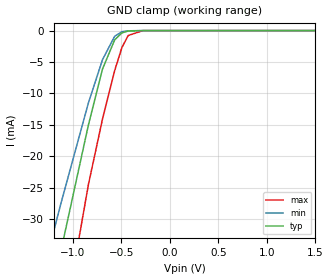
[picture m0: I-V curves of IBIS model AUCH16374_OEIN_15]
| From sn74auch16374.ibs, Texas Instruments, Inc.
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[Model]   AUCH16374_OEIN_15
Model_type  Input
Vinl=0.49
Vinh=1.04
| variable   typ   min   max
C_comp   2.48pF   2.04pF   2.85pF
[Temperature Range]   40   100   -40
| Ambient temperature   25   85   -40
[Voltage range]   1.5   1.4   1.6
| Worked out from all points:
|   GND clamp passes 1 mA (typ) near -0.55 V on its own axis
[GND Clamp]
| AUCH16374_OEIN_15
|   Voltage   I(typ)   I(min)   I(max)
-3.6V     -222.3mA   -186.1mA   -267.5mA
-1.505V   -63.42mA   -50.72mA   -83.44mA
-1.325V   -49.94mA   -39.61mA   -67.39mA
-1.17V    -38.46mA   -30.25mA   -53.55mA
-1.12V    -34.79mA   -27.28mA   -49.08mA
-840mV    -14.98mA   -11.48mA   -24.46mA
-695mV    -6.114mA   -4.621mA   -14.06mA
-570mV    -1.487mA   -911.6uA   -6.381mA
-495mV    -364.6uA   -178.8uA   -2.692mA
-430mV    -73.19uA   -34.73uA   -776.9uA
-280mV    -781.4nA   -556.3nA   -5.358uA
1.5V      165.9pA    258.5pA    172.1pA
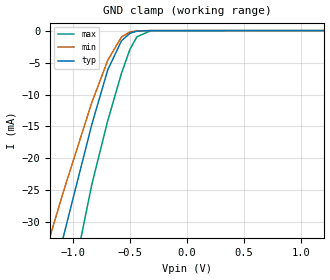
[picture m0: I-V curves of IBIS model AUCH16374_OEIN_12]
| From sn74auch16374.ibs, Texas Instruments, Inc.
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[Model]   AUCH16374_OEIN_12
Model_type  Input
Vinl=0.385
Vinh=0.845
| variable   typ   min   max
C_comp   2.51pF   2.11pF   2.86pF
[Temperature Range]   40   100   -40
| Ambient temperature   25   85   -40
[Voltage range]   1.2   1.1   1.3
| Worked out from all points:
|   GND clamp passes 1 mA (typ) near -0.55 V on its own axis
[GND Clamp]
| AUCH16374_OEIN_12
|   Voltage   I(typ)   I(min)   I(max)
-3.6V     -222.3mA   -186.1mA   -267.5mA
-1.445V   -58.91mA   -46.99mA   -78.09mA
-1.275V   -46.22mA   -36.57mA   -62.93mA
-1.11V    -34.06mA   -26.69mA   -48.19mA
-1.075V   -31.52mA   -24.64mA   -45.06mA
-835mV    -14.65mA   -11.22mA   -24.05mA
-695mV    -6.114mA   -4.621mA   -14.06mA
-575mV    -1.603mA   -998.8uA   -6.664mA
-500mV    -407.1uA   -201.6uA   -2.896mA
-440mV    -95.43uA   -45.03uA   -977.4uA
-320mV    -2.85uA    -1.742uA   -25.53uA
1.2V      133.3pA    223pA      123.7pA
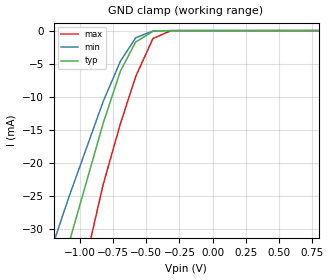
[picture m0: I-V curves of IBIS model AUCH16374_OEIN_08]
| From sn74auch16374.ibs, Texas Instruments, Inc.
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[Model]   AUCH16374_OEIN_08
Model_type  Input
Vinl=0
Vinh=0.8
| variable   typ   min   max
C_comp   2.54pF   2.21pF   2.84pF
[Temperature Range]   40   100   -40
| Ambient temperature   25   85   -40
[Voltage range]   0.8   0.8   0.8
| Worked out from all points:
|   GND clamp passes 1 mA (typ) near -0.55 V on its own axis
[GND Clamp]
| AUCH16374_OEIN_08
|   Voltage   I(typ)   I(min)   I(max)
-3.6V     -222.3mA   -186.1mA   -267.5mA
-1.455V   -59.66mA   -47.61mA   -78.99mA
-1.32V    -49.56mA   -39.31mA   -66.95mA
-1.275V   -46.22mA   -36.57mA   -62.93mA
-1.115V   -34.43mA   -26.99mA   -48.63mA
-1.08V    -31.88mA   -24.93mA   -45.51mA
-825mV    -13.98mA   -10.7mA    -23.23mA
-695mV    -6.114mA   -4.621mA   -14.06mA
-580mV    -1.724mA   -1.092mA   -6.949mA
-450mV    -123.7uA   -58.25uA   -1.212mA
-315mV    -2.431uA   -1.513uA   -21.15uA
800mV     96.17pA    179.1pA    76.88pA
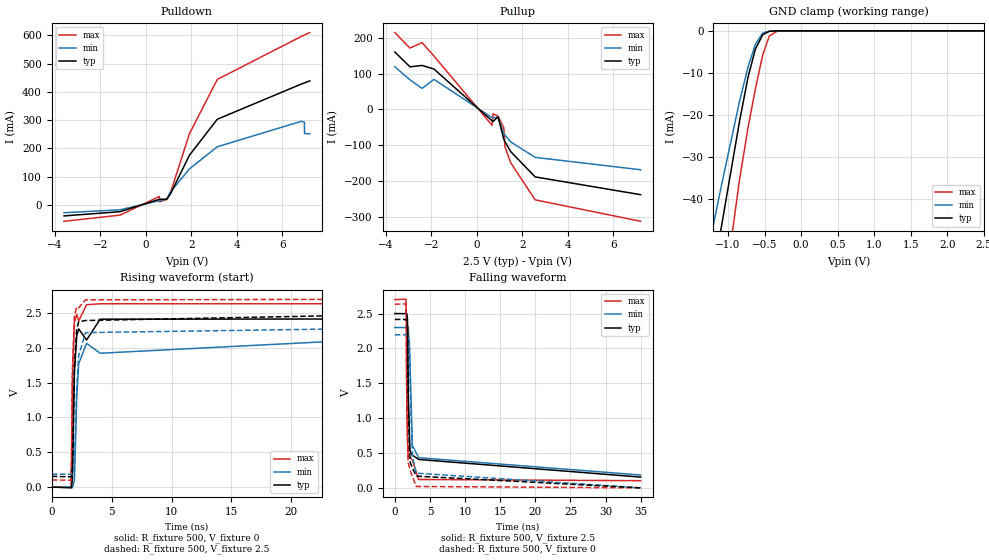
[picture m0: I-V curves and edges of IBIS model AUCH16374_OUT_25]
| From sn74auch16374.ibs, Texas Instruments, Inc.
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[Model]   AUCH16374_OUT_25
Model_type  3-state
Enable   Active-Low
Vref =   0
Rref =   500
Cref =   30p
Vmeas =   1.25
| variable   typ   min   max
C_comp   5.21pF   4.67pF   5.45pF
| C_pullup   7.72pF   4.63pF   11.90pF
| C_pulldown   6.68pF   4.66pF   15.29pF
| C_tri-state   5.21pF   4.67pF   5.45pF
[Temperature Range]   40   100   -40
| Ambient temperature   25   85   -40
[Voltage range]   2.5   2.3   2.7
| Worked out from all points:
|   slope of the pulldown table from 0 to 0.375 V, typ, clamps not added: 30.7 ohm
|   slope of the pullup table from 0 to 0.375 V, typ, clamps not added: 19 ohm
|   GND clamp passes 1 mA (typ) near -0.53 V on its own axis
|   rising waveform, R_fixture 500, V_fixture 0: 20-80 % time 202ps typ, 281ps min, 145ps max; typ from 0 V to 2.42 V
|   falling waveform, R_fixture 500, V_fixture 2.5: 20-80 % time 248ps typ, 345ps min, 180ps max; typ from 2.5 V to 0.154 V
|   rising waveform, R_fixture 500, V_fixture 2.5: 20-80 % time 206ps typ, 288ps min, 146ps max; typ from 0.154 V to 2.5 V
|   falling waveform, R_fixture 500, V_fixture 0: 20-80 % time 269ps typ, 377ps min, 184ps max; typ from 2.42 V to 0 V
[GND Clamp]
| AUCH16374_OUT_25
|   Voltage   I(typ)   I(min)   I(max)
-3.6V     -318.7mA   -267.2mA   -388.7mA
-1.515V   -91.86mA   -73.92mA   -122.2mA
-1.455V   -85.39mA   -68.57mA   -114.5mA
-1.295V   -68.26mA   -54.47mA   -93.72mA
-1.105V   -48.18mA   -38.11mA   -69.04mA
-840mV    -21.35mA   -16.65mA   -35.22mA
-725mV    -11mA      -8.581mA   -23.02mA
-625mV    -4.332mA   -3.19mA    -13.84mA
-525mV    -969.3uA   -536.9uA   -5.77mA
-435mV    -119.4uA   -67.05uA   -1.249mA
-325mV    -4.914uA   -5.522uA   -43.94uA
2.5V      1.045nA    211.8nA    1.502nA
[Pulldown]
| AUCH16374_OUT_25
|   Voltage   I(typ)   I(min)   I(max)
-3.6V     -38.75mA   -27.46mA   -57.79mA
-1.14V    -23.79mA   -17.18mA   -36mA
590mV     19.92mA    14.98mA    30.03mA
600mV     20.28mA    15.25mA    11.17mA
910mV     20.16mA    20.33mA    19.24mA
1.07V     37.88mA    45.66mA    41.07mA
1.915V    176.4mA    127.8mA    252.5mA
3.135V    303.2mA    205.9mA    444mA
6.825V    427.7mA    295.8mA    596.2mA
6.965V    431.9mA    293mA      601.3mA
6.97V     432.1mA    252.7mA    601.5mA
7.2V      439mA      251.9mA    609.9mA
[Pullup]
| AUCH16374_OUT_25
|   Voltage   I(typ)   I(min)   I(max)
-3.6V     160mA      119mA      214.2mA
-2.935V   118.6mA    82.49mA    170.9mA
-2.405V   122.6mA    58.64mA    186.2mA
-1.88V    112.5mA    83.79mA    148.8mA
670mV     -31.69mA   -22.93mA   -44.2mA
720mV     -33.47mA   -24.18mA   -12.23mA
935mV     -20.74mA   -21.43mA   -18.64mA
1.19V     -83.17mA   -67.47mA   -51.41mA
1.235V    -89.46mA   -71.21mA   -103.5mA
1.49V     -117.6mA   -90.51mA   -148.5mA
2.565V    -188.1mA   -133.7mA   -252.1mA
7.2V      -237.7mA   -168.2mA   -311.9mA
[Ramp]
| AUCH16374_OUT_25
| variable   typ   min   max
dV/dt_r   1.46/2.03E-10   1.33/2.84E-10   1.59/1.46E-10
dV/dt_f   1.41/2.50E-10   1.27/3.50E-10   1.56/1.81E-10
R_load = 500
[Rising Waveform]
| AUCH16374_OUT_25
R_fixture =   500
C_fixture =   0
L_fixture =   0
V_fixture =   0
V_fixture_min = 0
V_fixture_max = 0
|   Time   V(typ)   V(min)   V(max)
0s        12.33nV    36.82nV    2.005nV
1.605ns   -8.878mV   960uV      -6.308mV
1.65ns    -10.62mV   -921uV     261.7mV
1.73ns    122mV      -8.948mV   1.584V
1.895ns   1.639V     93.43mV    2.368V
2.09ns    2.175V     1.296V     2.481V
2.255ns   2.272V     1.774V     2.387V
2.905ns   2.113V     2.065V     2.62V
4.045ns   2.412V     1.923V     2.633V
34.99ns   2.416V     2.195V     2.634V
[Falling Waveform]
| AUCH16374_OUT_25
R_fixture =   500
C_fixture =   0
L_fixture =   0
V_fixture =   2.5
V_fixture_min = 2.3
V_fixture_max = 2.7
|   Time   V(typ)   V(min)   V(max)
0s        2.5V       2.3V       2.7V
1.585ns   2.499V     2.3V       2.707V
1.64ns    2.498V     2.3V       2.436V
1.71ns    2.5V       2.3V       1.196V
1.8ns     2.423V     2.299V     749.3mV
1.915ns   1.301V     2.298V     425.9mV
2.16ns    525.1mV    1.817V     441.9mV
2.495ns   469.6mV    609.5mV    397.7mV
3.395ns   407.3mV    432.3mV    120.3mV
34.99ns   154.5mV    184.4mV    102.7mV
[Rising Waveform]
| AUCH16374_OUT_25
R_fixture =   500
C_fixture =   0
L_fixture =   0
V_fixture =   2.5
V_fixture_min = 2.3
V_fixture_max = 2.7
|   Time   V(typ)   V(min)   V(max)
0s        154.5mV    184.4mV    102.6mV
1.605ns   147.4mV    185.2mV    99.53mV
1.65ns    148.6mV    183.8mV    388.7mV
1.71ns    225.9mV    179.5mV    1.425V
1.74ns    377.9mV    177.6mV    1.744V
1.89ns    1.706V     305.5mV    2.441V
2.075ns   2.257V     1.371V     2.589V
2.245ns   2.374V     1.884V     2.576V
2.82ns    2.393V     2.219V     2.69V
34.99ns   2.5V       2.3V       2.7V
[Falling Waveform]
| AUCH16374_OUT_25
R_fixture =   500
C_fixture =   0
L_fixture =   0
V_fixture =   0
V_fixture_min = 0
V_fixture_max = 0
|   Time   V(typ)   V(min)   V(max)
0s        2.416V     2.195V     2.634V
1.585ns   2.415V     2.195V     2.639V
1.71ns    2.414V     2.195V     1.151V
1.805ns   2.306V     2.194V     657.2mV
1.9ns     1.373V     2.192V     360.8mV
2.075ns   589.7mV    2.099V     293.3mV
2.2ns     363.5mV    1.381V     253.2mV
2.52ns    280.7mV    446mV      157mV
3.06ns    168.3mV    210.8mV    19.86mV
34.99ns   28.62uV    1.369uV    13.32uV
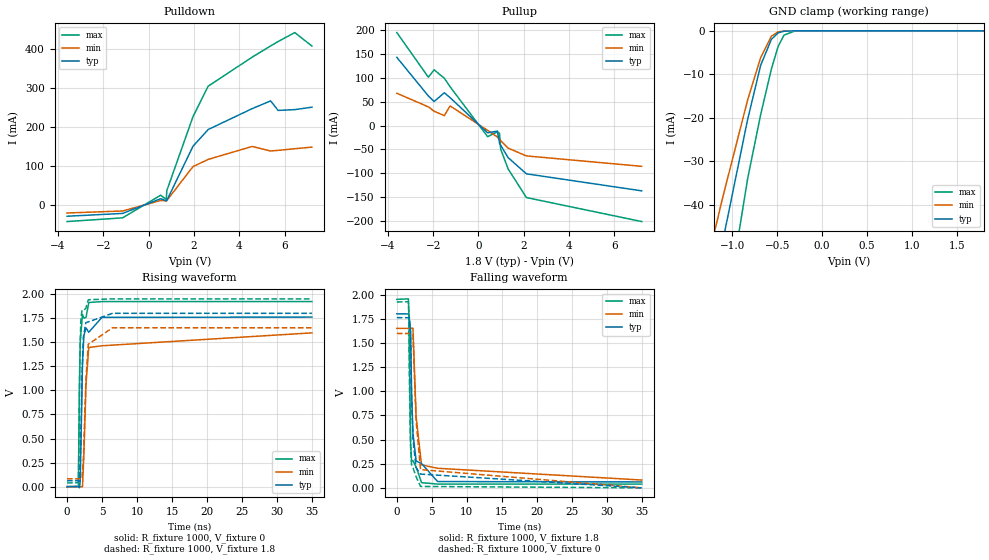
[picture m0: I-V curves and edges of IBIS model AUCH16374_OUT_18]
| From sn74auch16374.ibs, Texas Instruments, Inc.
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[Model]   AUCH16374_OUT_18
Model_type  3-state
Enable   Active-Low
Vref =   0
Rref =   1000
Cref =   30p
Vmeas =   0.9
| variable   typ   min   max
C_comp   5.42pF   4.87pF   5.64pF
| C_pullup   6.28pF   0.99pF   11.81pF
| C_pulldown   6.13pF   3.50pF   13.44pF
| C_tri-state   5.42pF   4.87pF   5.64pF
[Temperature Range]   40   100   -40
| Ambient temperature   25   85   -40
[Voltage range]   1.8   1.65   1.95
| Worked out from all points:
|   slope of the pulldown table from 0 to 0.27 V, typ, clamps not added: 34.2 ohm
|   slope of the pullup table from 0 to 0.27 V, typ, clamps not added: 24.9 ohm
|   GND clamp passes 1 mA (typ) near -0.53 V on its own axis
|   rising waveform, R_fixture 1000, V_fixture 0: 20-80 % time 313ps typ, 474ps min, 203ps max; typ from 0 V to 1.76 V
|   falling waveform, R_fixture 1000, V_fixture 1.8: 20-80 % time 399ps typ, 621ps min, 241ps max; typ from 1.8 V to 0.061 V
|   rising waveform, R_fixture 1000, V_fixture 1.8: 20-80 % time 310ps typ, 474ps min, 201ps max; typ from 0.061 V to 1.8 V
|   falling waveform, R_fixture 1000, V_fixture 0: 20-80 % time 398ps typ, 625ps min, 241ps max; typ from 1.76 V to 0 V
[GND Clamp]
| AUCH16374_OUT_18
|   Voltage   I(typ)   I(min)   I(max)
-3.6V     -318.7mA   -267.2mA   -388.7mA
-1.48V    -88.08mA   -70.8mA    -117.7mA
-1.435V   -83.24mA   -66.8mA    -111.9mA
-1.3V     -68.79mA   -54.91mA   -94.37mA
-1.105V   -48.18mA   -38.11mA   -69.04mA
-830mV    -20.4mA    -15.9mA    -34.03mA
-685mV    -7.944mA   -6.173mA   -19.28mA
-565mV    -1.95mA    -1.225mA   -8.764mA
-490mV    -463.8uA   -241.2uA   -3.576mA
-425mV    -91.37uA   -53.49uA   -985.3uA
-300mV    -2.288uA   -2.897uA   -16.98uA
1.8V      674.8pA    45.17nA    747.9pA
[Pulldown]
| AUCH16374_OUT_18
|   Voltage   I(typ)   I(min)   I(max)
-3.6V     -28.49mA   -20.22mA   -42.08mA
-1.15V    -21.28mA   -15.02mA   -32.6mA
530mV     16.28mA    11.83mA    25.26mA
780mV     11.06mA    10.81mA    14.1mA
800mV     11.7mA     11.72mA    36.72mA
1.955V    150.3mA    98.42mA    225.9mA
2.625V    193.2mA    116.8mA    304mA
4.56V     246.5mA    149.9mA    378.1mA
5.38V     266.4mA    138.3mA    406.9mA
5.71V     242.1mA    140mA      418.2mA
6.445V    244.1mA    144.1mA    441.1mA
7.2V      250.4mA    148.3mA    406.7mA
[Pullup]
| AUCH16374_OUT_18
|   Voltage   I(typ)   I(min)   I(max)
-3.6V     143.4mA    67.81mA    195.5mA
-2.21V    62.22mA    39.25mA    101.7mA
-1.955V   50.53mA    30.07mA    117.2mA
-1.505V   68.89mA    20.87mA    99.46mA
-1.25V    58.62mA    41.27mA    81.57mA
405mV     -15.38mA   -10.2mA    -23.47mA
835mV     -11.64mA   -24.19mA   -13.09mA
930mV     -37.45mA   -29.05mA   -16.21mA
980mV     -41.44mA   -31.73mA   -49.64mA
1.31V     -67.6mA    -47.58mA   -91.39mA
2.115V    -101.6mA   -63.91mA   -151.5mA
7.2V      -137.4mA   -85.82mA   -202mA
[Ramp]
| AUCH16374_OUT_18
| variable   typ   min   max
dV/dt_r   1.06/3.19E-10   0.97/4.78E-10   1.15/2.05E-10
dV/dt_f   1.05/4.00E-10   0.95/6.22E-10   1.15/2.43E-10
R_load = 1000
[Rising Waveform]
| AUCH16374_OUT_18
R_fixture =   1000
C_fixture =   0
L_fixture =   0
V_fixture =   0
V_fixture_min = 0
V_fixture_max = 0
|   Time   V(typ)   V(min)   V(max)
0s        9.675nV    33.63nV    1.209nV
1.625ns   1.147mV    591.7uV    3.39mV
1.78ns    -12.14mV   1.509mV    1.042V
1.89ns    62.48mV    54.87uV    1.513V
2.21ns    1.275V     -292.6uV   1.788V
2.41ns    1.569V     336.3mV    1.75V
2.72ns    1.648V     1.068V     1.758V
3.105ns   1.603V     1.445V     1.912V
4.99ns    1.758V     1.463V     1.922V
34.99ns   1.761V     1.597V     1.922V
[Falling Waveform]
| AUCH16374_OUT_18
R_fixture =   1000
C_fixture =   0
L_fixture =   0
V_fixture =   1.8
V_fixture_min = 1.65
V_fixture_max = 1.95
|   Time   V(typ)   V(min)   V(max)
0s        1.8V       1.65V      1.95V
1.65ns    1.799V     1.65V      1.955V
1.71ns    1.799V     1.65V      1.837V
1.97ns    1.619V     1.649V     456.8mV
2.105ns   983.8mV    1.651V     277.4mV
2.305ns   563.6mV    1.651V     280.8mV
2.76ns    277.6mV    735.2mV    217.3mV
3.525ns   252.1mV    238mV      53.83mV
5.825ns   65.16mV    202.4mV    39.08mV
34.99ns   61.08mV    81.02mV    38.7mV
[Rising Waveform]
| AUCH16374_OUT_18
R_fixture =   1000
C_fixture =   0
L_fixture =   0
V_fixture =   1.8
V_fixture_min = 1.65
V_fixture_max = 1.95
|   Time   V(typ)   V(min)   V(max)
0s        61.05mV    81.01mV    38.68mV
1.62ns    62.16mV    81.53mV    41.06mV
1.815ns   56.03mV    82.36mV    1.262V
1.97ns    479.5mV    78.1mV     1.727V
2.135ns   1.14V      83.01mV    1.831V
2.335ns   1.551V     280.6mV    1.831V
2.685ns   1.702V     1.096V     1.85V
3.035ns   1.711V     1.478V     1.941V
6.51ns    1.8V       1.65V      1.95V
34.99ns   1.8V       1.65V      1.95V
[Falling Waveform]
| AUCH16374_OUT_18
R_fixture =   1000
C_fixture =   0
L_fixture =   0
V_fixture =   0
V_fixture_min = 0
V_fixture_max = 0
|   Time   V(typ)   V(min)   V(max)
0s        1.761V     1.597V     1.922V
1.65ns    1.76V      1.597V     1.926V
1.71ns    1.76V      1.597V     1.804V
1.8ns     1.763V     1.597V     1.08V
1.965ns   1.587V     1.596V     431.4mV
2.1ns     967.8mV    1.598V     242.2mV
2.305ns   509.7mV    1.587V     208.8mV
2.745ns   209.2mV    701.9mV    116.2mV
3.39ns    142.3mV    188.6mV    14.43mV
34.99ns   35.76uV    3.104uV    16.21uV
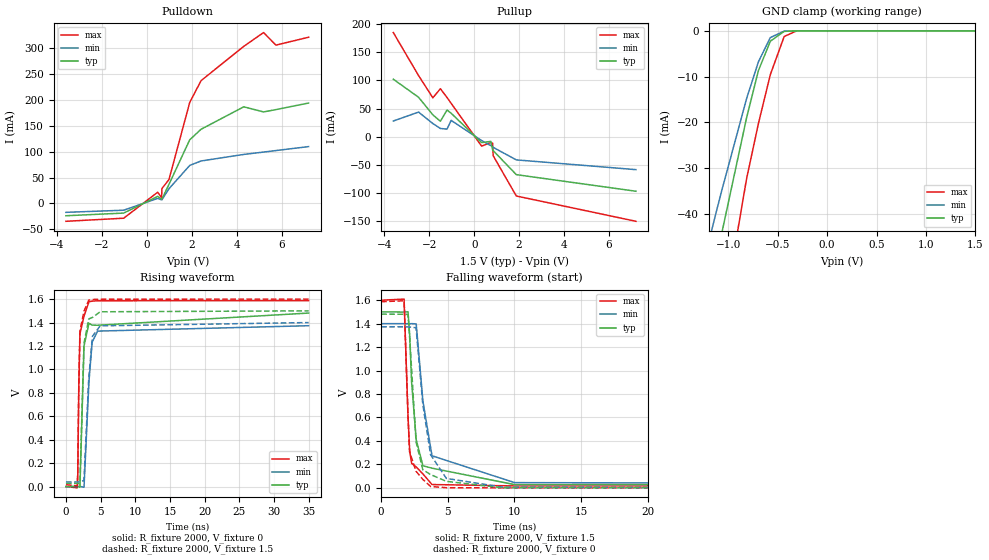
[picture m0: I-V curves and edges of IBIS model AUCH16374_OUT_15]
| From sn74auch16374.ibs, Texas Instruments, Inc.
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[Model]   AUCH16374_OUT_15
Model_type  3-state
Enable   Active-Low
Vref =   0
Rref =   2000
Cref =   15p
Vmeas =   0.75
| variable   typ   min   max
C_comp   5.52pF   4.97pF   5.78pF
| C_pullup   4.89pF   0.40pF   12.19pF
| C_pulldown   6.35pF   5.34pF   11.48pF
| C_tri-state   5.52pF   4.97pF   5.78pF
[Temperature Range]   40   100   -40
| Ambient temperature   25   85   -40
[Voltage range]   1.5   1.4   1.6
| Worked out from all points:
|   slope of the pulldown table from 0 to 0.225 V, typ, clamps not added: 37.2 ohm
|   slope of the pullup table from 0 to 0.225 V, typ, clamps not added: 30 ohm
|   GND clamp passes 1 mA (typ) near -0.53 V on its own axis
|   rising waveform, R_fixture 2000, V_fixture 0: 20-80 % time 406ps typ, 628ps min, 254ps max; typ from 0 V to 1.48 V
|   falling waveform, R_fixture 2000, V_fixture 1.5: 20-80 % time 539ps typ, 857ps min, 301ps max; typ from 1.5 V to 0.027 V
|   rising waveform, R_fixture 2000, V_fixture 1.5: 20-80 % time 401ps typ, 624ps min, 250ps max; typ from 0.027 V to 1.5 V
|   falling waveform, R_fixture 2000, V_fixture 0: 20-80 % time 537ps typ, 853ps min, 302ps max; typ from 1.48 V to 0 V
[GND Clamp]
| AUCH16374_OUT_15
|   Voltage   I(typ)   I(min)   I(max)
-3.6V     -318.7mA   -267.2mA   -388.7mA
-1.465V   -86.47mA   -69.46mA   -115.8mA
-1.33V    -71.99mA   -57.53mA   -98.26mA
-1.29V    -67.72mA   -54.03mA   -93.07mA
-1.125V   -50.28mA   -39.81mA   -71.64mA
-1.075V   -45.06mA   -35.58mA   -65.15mA
-815mV    -18.98mA   -14.79mA   -32.28mA
-695mV    -8.667mA   -6.748mA   -20.21mA
-575mV    -2.269mA   -1.473mA   -9.572mA
-435mV    -119.4uA   -67.05uA   -1.249mA
-310mV    -3.104uA   -3.767uA   -25uA
1.5V      550.3pA    9.378nA    545.2pA
[Pulldown]
| AUCH16374_OUT_15
|   Voltage   I(typ)   I(min)   I(max)
-3.6V     -23.87mA   -17.26mA   -34.61mA
-1.03V    -18.71mA   -13.15mA   -28.63mA
485mV     13.68mA    9.737mA    21.72mA
660mV     8.179mA    6.953mA    10.96mA
670mV     8.319mA    7.1mA      28.79mA
985mV     36.88mA    28.41mA    46.12mA
1.91V     123.2mA    73.57mA    195.6mA
2.415V    143.6mA    82.17mA    237.7mA
4.315V    187mA      94.84mA    304mA
5.195V    177.1mA    99.4mA     330.7mA
5.745V    181.6mA    102.3mA    306.4mA
7.2V      194.3mA    110mA      321.7mA
[Pullup]
| AUCH16374_OUT_15
|   Voltage   I(typ)   I(min)   I(max)
-3.6V     102.1mA    27.92mA    184.9mA
-2.475V   70.01mA    43.77mA    108.5mA
-1.84V    38.84mA    23.47mA    69.11mA
-1.505V   27.39mA    14.66mA    85.19mA
-1.21V    47.39mA    13.5mA     69.72mA
-1.025V   41.71mA    29.01mA    59.25mA
330mV     -10.46mA   -6.758mA   -16.68mA
740mV     -8.272mA   -15.76mA   -10.25mA
820mV     -23.65mA   -18mA      -11.49mA
845mV     -24.61mA   -18.86mA   -33.67mA
1.875V    -67.28mA   -41.09mA   -105.2mA
7.2V      -96.75mA   -58.41mA   -150.1mA
[Ramp]
| AUCH16374_OUT_15
| variable   typ   min   max
dV/dt_r   0.89/4.08E-10   0.83/6.35E-10   0.96/2.56E-10
dV/dt_f   0.89/5.42E-10   0.82/8.61E-10   0.96/3.02E-10
R_load = 2000
[Rising Waveform]
| AUCH16374_OUT_15
R_fixture =   2000
C_fixture =   0
L_fixture =   0
V_fixture =   0
V_fixture_min = 0
V_fixture_max = 0
|   Time   V(typ)   V(min)   V(max)
0s        8.895nV    33.88nV    950.2pV
1.625ns   617.8uV    -27.17uV   -11.08mV
1.7ns     1.047mV    79.67uV    89.27mV
1.85ns    -2.286mV   742.4uV    832.5mV
2.015ns   -6.79mV    1.373mV    1.303V
2.605ns   1.2V       -5.961mV   1.455V
3.315ns   1.394V     896.3mV    1.577V
3.78ns    1.378V     1.232V     1.583V
4.56ns    1.377V     1.327V     1.586V
34.99ns   1.481V     1.373V     1.587V
[Falling Waveform]
| AUCH16374_OUT_15
R_fixture =   2000
C_fixture =   0
L_fixture =   0
V_fixture =   1.5
V_fixture_min = 1.4
V_fixture_max = 1.6
|   Time   V(typ)   V(min)   V(max)
0s        1.5V       1.4V       1.6V
1.72ns    1.499V     1.4V       1.609V
2.015ns   1.501V     1.399V     610.3mV
2.14ns    1.302V     1.399V     314.8mV
2.285ns   901mV      1.4V       208.5mV
2.63ns    411mV      1.398V     178.3mV
3.135ns   188.1mV    737.7mV    118.7mV
3.815ns   168mV      273.6mV    28.4mV
10.02ns   27.54mV    44.65mV    16.5mV
34.99ns   27.21mV    38.76mV    16.42mV
[Rising Waveform]
| AUCH16374_OUT_15
R_fixture =   2000
C_fixture =   0
L_fixture =   0
V_fixture =   1.5
V_fixture_min = 1.4
V_fixture_max = 1.6
|   Time   V(typ)   V(min)   V(max)
0s        27.17mV    38.75mV    16.4mV
1.625ns   27.78mV    38.73mV    6.212mV
1.7ns     28.18mV    38.83mV    115.3mV
1.85ns    25.16mV    39.47mV    861.6mV
2.015ns   28.79mV    40mV       1.327V
2.595ns   1.223V     51.35mV    1.497V
3.29ns    1.431V     928.3mV    1.592V
3.825ns   1.444V     1.283V     1.597V
4.935ns   1.492V     1.372V     1.599V
34.99ns   1.5V       1.4V       1.6V
[Falling Waveform]
| AUCH16374_OUT_15
R_fixture =   2000
C_fixture =   0
L_fixture =   0
V_fixture =   0
V_fixture_min = 0
V_fixture_max = 0
|   Time   V(typ)   V(min)   V(max)
0s        1.481V     1.373V     1.587V
1.72ns    1.48V      1.373V     1.595V
2.015ns   1.478V     1.372V     602.7mV
2.135ns   1.286V     1.371V     304.9mV
2.62ns    391.5mV    1.365V     141.1mV
3.125ns   154.8mV    713.3mV    72.54mV
3.71ns    113.3mV    282.8mV    11.94mV
4.895ns   55.47mV    80.48mV    1.161mV
9.095ns   434.6uV    6.38mV     118.3uV
34.99ns   40.36uV    5.328uV    17.73uV
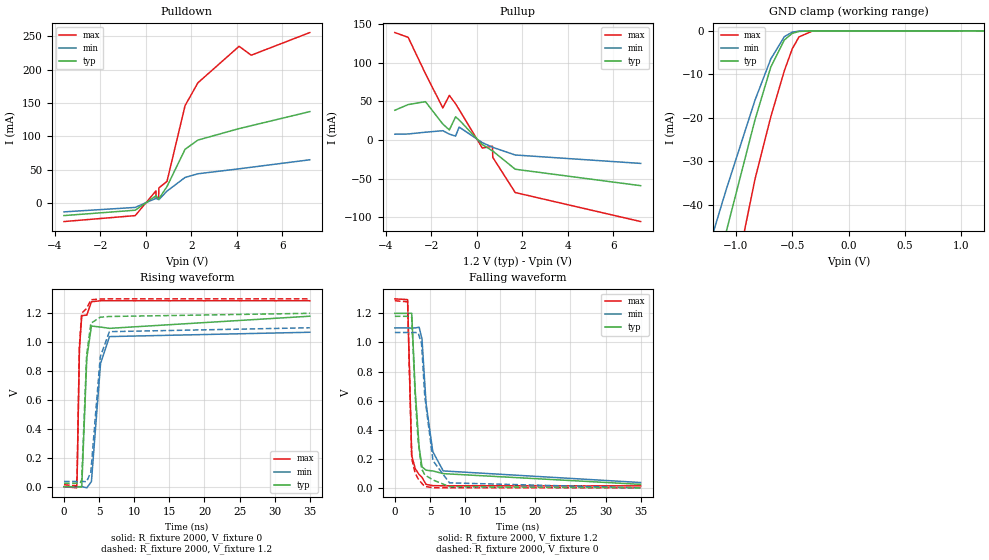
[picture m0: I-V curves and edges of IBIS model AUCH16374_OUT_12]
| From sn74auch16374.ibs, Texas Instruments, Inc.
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[Model]   AUCH16374_OUT_12
Model_type  3-state
Enable   Active-Low
Vref =   0
Rref =   2000
Cref =   15p
Vmeas =   0.6
| variable   typ   min   max
C_comp   5.62pF   5.11pF   5.87pF
| C_pullup   4.88pF   0.64pF   9.68pF
| C_pulldown   6.17pF   5.46pF   7.21pF
| C_tri-state   5.62pF   5.11pF   5.87pF
[Temperature Range]   40   100   -40
| Ambient temperature   25   85   -40
[Voltage range]   1.2   1.1   1.3
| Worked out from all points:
|   slope of the pulldown table from 0 to 0.18 V, typ, clamps not added: 42.1 ohm
|   slope of the pullup table from 0 to 0.18 V, typ, clamps not added: 38.3 ohm
|   GND clamp passes 1 mA (typ) near -0.53 V on its own axis
|   rising waveform, R_fixture 2000, V_fixture 0: 20-80 % time 587ps typ, 992ps min, 323ps max; typ from 0 V to 1.18 V
|   falling waveform, R_fixture 2000, V_fixture 1.2: 20-80 % time 867ps typ, 1.35ns min, 424ps max; typ from 1.2 V to 0.024 V
|   rising waveform, R_fixture 2000, V_fixture 1.2: 20-80 % time 578ps typ, 995ps min, 317ps max; typ from 0.024 V to 1.2 V
|   falling waveform, R_fixture 2000, V_fixture 0: 20-80 % time 854ps typ, 1.28ns min, 419ps max; typ from 1.18 V to 0 V
[GND Clamp]
| AUCH16374_OUT_12
|   Voltage   I(typ)   I(min)   I(max)
-3.6V     -318.7mA   -267.2mA   -388.7mA
-1.46V    -85.93mA   -69.02mA   -115.1mA
-1.285V   -67.19mA   -53.6mA    -92.42mA
-1.12V    -49.75mA   -39.38mA   -70.99mA
-1.085V   -46.1mA    -36.42mA   -66.44mA
-830mV    -20.4mA    -15.9mA    -34.03mA
-690mV    -8.302mA   -6.458mA   -19.75mA
-570mV    -2.106mA   -1.345mA   -9.166mA
-500mV    -579.1uA   -304.4uA   -4.154mA
-440mV    -136.2uA   -75.16uA   -1.399mA
-320mV    -4.216uA   -4.869uA   -36.5uA
1.2V      442.5pA    9.259nA    389.9pA
[Pulldown]
| AUCH16374_OUT_12
|   Voltage   I(typ)   I(min)   I(max)
-3.6V     -19.18mA   -13.63mA   -28.17mA
-470mV    -11.13mA   -6.91mA    -19.23mA
440mV     10.48mA    6.706mA    17.92mA
445mV     10.59mA    6.769mA    6.318mA
560mV     5.857mA    4.698mA    8.209mA
570mV     5.97mA     4.786mA    22.41mA
925mV     24.38mA    17.54mA    32.09mA
1.72V     80.36mA    38.11mA    146mA
2.285V    94.25mA    43.63mA    180.3mA
4.095V    111.5mA    51.07mA    235.1mA
4.625V    115.8mA    53.41mA    221.7mA
7.2V      137mA      64.62mA    255.7mA
[Pullup]
| AUCH16374_OUT_12
|   Voltage   I(typ)   I(min)   I(max)
-3.6V     38.61mA    7.555mA    139.2mA
-3.015V   45.91mA    7.851mA    133.1mA
-2.255V   49.73mA    10.14mA    86.01mA
-1.49V    20.68mA    12.09mA    41.55mA
-1.205V   13.08mA    7.704mA    57.86mA
-930mV    30.05mA    5.088mA    46.93mA
-775mV    26.1mA     16.83mA    39.5mA
245mV     -5.916mA   -3.381mA   -10.43mA
690mV     -14.05mA   -9.319mA   -7.997mA
705mV     -14.25mA   -9.473mA   -22.45mA
1.69V     -37.81mA   -19.38mA   -68.01mA
7.2V      -59.11mA   -30.28mA   -105.6mA
[Ramp]
| AUCH16374_OUT_12
| variable   typ   min   max
dV/dt_r   0.71/5.92E-10   0.65/1.00E-09   0.78/3.26E-10
dV/dt_f   0.71/8.68E-10   0.64/1.35E-09   0.77/4.28E-10
R_load = 2000
[Rising Waveform]
| AUCH16374_OUT_12
R_fixture =   2000
C_fixture =   0
L_fixture =   0
V_fixture =   0
V_fixture_min = 0
V_fixture_max = 0
|   Time   V(typ)   V(min)   V(max)
0s        8.336nV    36nV       765.5pV
1.8ns     294uV      -23.4uV    -7.529mV
1.87ns    582.2uV    -33.93uV   65.46mV
2.2ns     -1.506mV   533.8uV    956.3mV
2.53ns    -753.9uV   1.009mV    1.183V
3.25ns    891.9mV    -7.718mV   1.188V
3.905ns   1.112V     35.8mV     1.28V
5.205ns   1.105V     852.9mV    1.287V
6.475ns   1.096V     1.039V     1.287V
34.99ns   1.18V      1.069V     1.287V
[Falling Waveform]
| AUCH16374_OUT_12
R_fixture =   2000
C_fixture =   0
L_fixture =   0
V_fixture =   1.2
V_fixture_min = 1.1
V_fixture_max = 1.3
|   Time   V(typ)   V(min)   V(max)
0s        1.2V       1.1V       1.3V
1.82ns    1.2V       1.1V       1.295V
2.405ns   1.201V     1.099V     222.5mV
2.905ns   665.2mV    1.1V       131.8mV
3.46ns    281.2mV    1.105V     91.48mV
3.865ns   144.5mV    1.025V     72.41mV
4.45ns    121.6mV    579.7mV    23.64mV
5.405ns   116.3mV    249.1mV    15.21mV
6.89ns    97.81mV    116.5mV    14.2mV
34.99ns   24.03mV    36.64mV    13.88mV
[Rising Waveform]
| AUCH16374_OUT_12
R_fixture =   2000
C_fixture =   0
L_fixture =   0
V_fixture =   1.2
V_fixture_min = 1.1
V_fixture_max = 1.3
|   Time   V(typ)   V(min)   V(max)
0s        23.98mV    36.61mV    13.86mV
1.795ns   24.24mV    36.59mV    6.852mV
1.87ns    24.53mV    36.58mV    89.51mV
2.19ns    22.93mV    37.07mV    967.1mV
2.515ns   38.68mV    37.35mV    1.201V
3.22ns    909.9mV    34.33mV    1.233V
3.825ns   1.131V     101.7mV    1.294V
5.16ns    1.173V     898.4mV    1.299V
6.465ns   1.178V     1.073V     1.3V
34.99ns   1.2V       1.1V       1.3V
[Falling Waveform]
| AUCH16374_OUT_12
R_fixture =   2000
C_fixture =   0
L_fixture =   0
V_fixture =   0
V_fixture_min = 0
V_fixture_max = 0
|   Time   V(typ)   V(min)   V(max)
0s        1.18V      1.069V     1.287V
1.82ns    1.18V      1.069V     1.28V
2.405ns   1.174V     1.068V     201.6mV
2.885ns   643.8mV    1.069V     103.6mV
3.325ns   319.3mV    1.066V     61.51mV
3.81ns    131.4mV    989.3mV    33.1mV
4.26ns    89.3mV     632.3mV    9.631mV
5.43ns    54.31mV    187mV      971.2uV
7.78ns    8.018mV    34.13mV    203.9uV
34.99ns   49.37uV    15.7uV     19.35uV
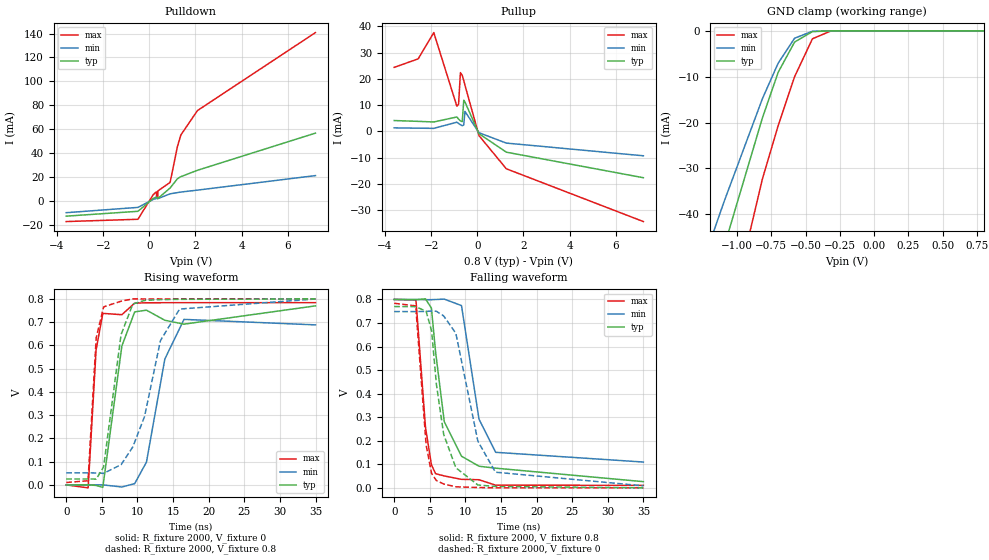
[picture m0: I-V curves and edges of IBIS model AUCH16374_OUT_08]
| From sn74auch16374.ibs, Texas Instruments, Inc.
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[Model]   AUCH16374_OUT_08
Model_type  3-state
Enable   Active-Low
Vref =   0
Rref =   2000
Cref =   15p
Vmeas =   0.4
| variable   typ   min   max
C_comp   5.72pF   5.24pF   5.98pF
| C_pullup   5.84pF   1.33pF   8.19pF
| C_pulldown   6.32pF   5.77pF   6.75pF
| C_tri-state   5.72pF   5.24pF   5.98pF
[Temperature Range]   40   100   -40
| Ambient temperature   25   85   -40
[Voltage range]   0.8   0.8   0.8
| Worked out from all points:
|   slope of the pulldown table from 0 to 0.12 V, typ, clamps not added: 77.5 ohm
|   slope of the pullup table from 0 to 0.12 V, typ, clamps not added: 92.7 ohm
|   GND clamp passes 1 mA (typ) near -0.53 V on its own axis
|   rising waveform, R_fixture 2000, V_fixture 0: 20-80 % time 1.75ns typ, 2.42ns min, 924ps max; typ from 0 V to 0.77 V
|   falling waveform, R_fixture 2000, V_fixture 0.8: 20-80 % time 2.66ns typ, 2.1ns min, 1.36ns max; typ from 0.8 V to 0.026 V
|   rising waveform, R_fixture 2000, V_fixture 0.8: 20-80 % time 1.81ns typ, 3.71ns min, 879ps max; typ from 0.025 V to 0.8 V
|   falling waveform, R_fixture 2000, V_fixture 0: 20-80 % time 2.19ns typ, 2.83ns min, 1.22ns max; typ from 0.77 V to 0 V
[GND Clamp]
| AUCH16374_OUT_08
|   Voltage   I(typ)   I(min)   I(max)
-3.6V     -318.7mA   -267.2mA   -388.7mA
-1.475V   -87.55mA   -70.35mA   -117.1mA
-1.34V    -73.06mA   -58.41mA   -99.56mA
-1.295V   -68.26mA   -54.47mA   -93.72mA
-1.125V   -50.28mA   -39.81mA   -71.64mA
-1.09V    -46.62mA   -36.85mA   -67.09mA
-815mV    -18.98mA   -14.79mA   -32.28mA
-700mV    -9.04mA    -7.043mA   -20.67mA
-580mV    -2.44mA    -1.608mA   -9.983mA
-450mV    -176.4uA   -94.62uA   -1.735mA
-315mV    -3.617uA   -4.286uA   -30.24uA
800mV     320.2pA    582.3pA    244.4pA
[Pulldown]
| AUCH16374_OUT_08
|   Voltage   I(typ)   I(min)   I(max)
-3.6V     -12.84mA   -9.953mA   -17.38mA
-495mV    -8.803mA   -5.523mA   -15.47mA
175mV     2.059mA    1.185mA    5.31mA
310mV     3.174mA    2.053mA    7.502mA
315mV     3.217mA    2.087mA    2.47mA
365mV     1.856mA    1.796mA    2.807mA
370mV     1.894mA    1.829mA    8.27mA
900mV     10.72mA    5.829mA    15.4mA
1.215V    18.4mA     6.852mA    45.18mA
1.365V    20.2mA     7.318mA    55.07mA
2.085V    25.54mA    8.939mA    75.52mA
7.2V      56.65mA    21.1mA     140.8mA
[Pullup]
| AUCH16374_OUT_08
|   Voltage   I(typ)   I(min)   I(max)
-3.6V     4.13mA     1.333mA    24.36mA
-2.56V    3.817mA    1.227mA    27.6mA
-1.885V   3.587mA    1.149mA    37.6mA
-885mV    5.478mA    3.491mA    9.6mA
-810mV    4.708mA    3.016mA    10.3mA
-730mV    3.982mA    2.544mA    22.37mA
-650mV    3.702mA    2.149mA    21.3mA
-585mV    11.85mA    2.417mA    19.32mA
-535mV    11.24mA    7.608mA    17.64mA
75mV      -881.4uA   -518.8uA   -1.613mA
1.26V     -7.908mA   -4.45mA    -14.23mA
7.2V      -17.63mA   -9.285mA   -34.31mA
[Ramp]
| AUCH16374_OUT_08
| variable   typ   min   max
dV/dt_r   0.47/1.76E-09   0.46/2.89E-09   0.48/9.31E-10
dV/dt_f   0.47/2.65E-09   0.42/2.11E-09   0.48/1.36E-09
R_load = 2000
[Rising Waveform]
| AUCH16374_OUT_08
R_fixture =   2000
C_fixture =   0
L_fixture =   0
V_fixture =   0
V_fixture_min = 0
V_fixture_max = 0
|   Time   V(typ)   V(min)   V(max)
0s        10.26nV    58.84nV    576.2pV
3.07ns    489.2uV    329.3nV    -12.48mV
4.185ns   -2.086mV   510.4uV    580.5mV
5.13ns    -10.58mV   388.8uV    737.6mV
7.805ns   597.3mV    -8.837mV   731.9mV
9.605ns   744mV      5.701mV    781.8mV
11.26ns   751.4mV    98.26mV    783.2mV
13.84ns   708mV      541.5mV    783.5mV
16.53ns   691.3mV    711.7mV    783.6mV
34.99ns   769.9mV    688.2mV    783.7mV
[Falling Waveform]
| AUCH16374_OUT_08
R_fixture =   2000
C_fixture =   0
L_fixture =   0
V_fixture =   0.8
V_fixture_min = 0.8
V_fixture_max = 0.8
|   Time   V(typ)   V(min)   V(max)
0s        800mV      800mV      800mV
3.055ns   798.8mV    800mV      797.9mV
4.395ns   802.5mV    799mV      256.9mV
5.225ns   763.3mV    799mV      98.22mV
5.81ns    577.2mV    799.8mV    60.19mV
7.035ns   280.6mV    801.3mV    50.58mV
9.45ns    134.4mV    774mV      36.18mV
11.91ns   91.81mV    291.5mV    34.48mV
14.25ns   83.57mV    150.9mV    11.3mV
34.99ns   26.3mV     109.6mV    10.63mV
[Rising Waveform]
| AUCH16374_OUT_08
R_fixture =   2000
C_fixture =   0
L_fixture =   0
V_fixture =   0.8
V_fixture_min = 0.8
V_fixture_max = 0.8
|   Time   V(typ)   V(min)   V(max)
0s        25.46mV    51.93mV    10.6mV
3.055ns   25.59mV    51.99mV    17.93mV
4.2ns     25.22mV    51.51mV    632.1mV
5.24ns    77.27mV    49.76mV    765.5mV
7.695ns   646.6mV    87.11mV    790mV
9.345ns   777.9mV    163.6mV    799.9mV
10.99ns   793.1mV    294.3mV    799.7mV
13.22ns   796.8mV    620.1mV    799.8mV
15.91ns   798mV      756.2mV    799.8mV
34.99ns   799.9mV    799.4mV    800mV
[Falling Waveform]
| AUCH16374_OUT_08
R_fixture =   2000
C_fixture =   0
L_fixture =   0
V_fixture =   0
V_fixture_min = 0
V_fixture_max = 0
|   Time   V(typ)   V(min)   V(max)
0s        770mV      748.6mV    783.8mV
3.02ns    769.4mV    748.5mV    772.7mV
4.48ns    750mV      749.2mV    182.9mV
5.25ns    667.2mV    750.7mV    60.78mV
5.935ns   437.5mV    749.7mV    30.87mV
6.945ns   227.4mV    730.1mV    16.48mV
8.655ns   85.35mV    656.4mV    4.419mV
11.75ns   12.14mV    198.1mV    1.459mV
14.22ns   6.005mV    66.53mV    159.8uV
34.99ns   146uV      8.557mV    30.12uV
